VERSION 5.6 ;
#  NOWIREEXTENSIONATPIN ON ;
  DIVIDERCHAR "/" ;
  BUSBITCHARS "[]" ;

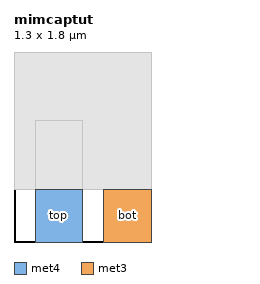
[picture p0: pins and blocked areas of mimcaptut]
MACRO mimcaptut
  CLASS BLOCK ;
  FOREIGN mimcaptut ;
  ORIGIN 0.000 0.000 ;
#  FOREIGN mimcaptut 0 0 ;
  SIZE 1.300 BY 1.800 ;
#  SYMMETRY X Y ;
#  SITE unithd ;
  PIN top
    DIRECTION INOUT ;
    USE SIGNAL ;
    PORT
      LAYER met4 ;
        RECT 0.2 0 0.65 0.5 ;
    END
  END top
  PIN bot
    DIRECTION INOUT ;
    USE SIGNAL ;
    PORT
      LAYER met3 ;
        RECT 0.85 0 1.3 0.5 ;
    END
  END bot
  OBS
      LAYER met3 ;
        RECT 0.000 0.500 1.300 1.800 ;
      LAYER met4 ;
        RECT 0.200 0.500 0.650 1.150 ;
  END
END mimcaptut
END LIBRARY
